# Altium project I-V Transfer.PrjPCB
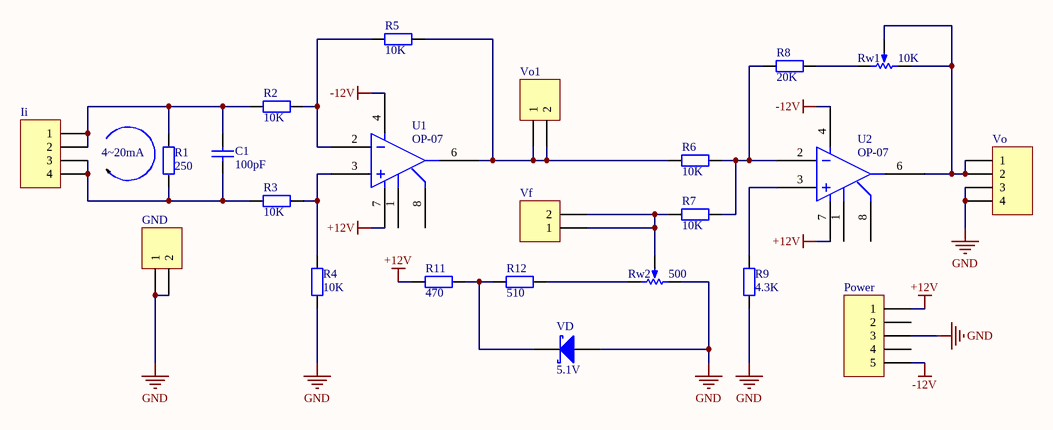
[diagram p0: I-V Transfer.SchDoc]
1 sheet, 23 parts. Net scope: global (net labels, ports and power ports of the same name join across sheets).
Board file: I-V Transfer.PcbDoc

## Sheet I-V Transfer.SchDoc
size A4

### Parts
C1  value 100pF  [RAD0.2]  (hidden comment: Cap)
GND  Header 2  [SIP-2]  (value not drawn)
Ii  Header 4  [SIP-4]  (value not drawn)
Power  Header 5  [POWER PLUG5]  (value not drawn)
R1  value 250  [AXIAL-0.4]  (hidden comment: Res2)
R2  value 10K  [AXIAL-0.4]  (hidden comment: Res2)
R3  value 10K  [AXIAL-0.4]  (hidden comment: Res2)
R4  value 10K  [AXIAL-0.4]  (hidden comment: Res2)
R5  value 10K  [AXIAL-0.4]  (hidden comment: Res2)
R6  value 10K  [AXIAL-0.4]  (hidden comment: Res2)
R7  value 10K  [AXIAL-0.4]  (hidden comment: Res2)
R8  value 20K  [AXIAL-0.4]  (hidden comment: Res2)
R9  value 4.3K  [AXIAL-0.4]  (hidden comment: Res2)
R11  value 470  [AXIAL-0.4]  (hidden comment: Res2)
R12  value 510  [AXIAL-0.4]  (hidden comment: Res2)
Rw1  value 10K  [VR5]  (hidden comment: RPot)
Rw2  value 500  [VR5]  (hidden comment: RPot)
U1  OP-07  [DIP-8]
U2  OP-07  [DIP-8]
VD  5.1V  [DIODE0.4]
Vf  Header 2  [SIP-2]  (value not drawn)
Vo  Header 4  [SIP-4]  (value not drawn)
Vo1  Header 2  [SIP-2]  (value not drawn)

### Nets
+12V: Power.1 R11.1 U1.7 U2.7
-12V: Power.5 U1.4 U2.4
GND: GND.1 GND.2 Power.3 R4.1 R9.1 Rw2.1(TOP) VD.1(A) Vo.3 Vo.4
NetC1_1: C1.1 Ii.3 Ii.4 R1.1 R3.1
NetC1_2: C1.2 Ii.1 Ii.2 R1.2 R2.1
NetR2_2: R2.2 R5.1 U1.2
NetR3_2: R3.2 R4.2 U1.3
NetR5_2: R5.2 R6.1 U1.6 Vo1.1 Vo1.2
NetR6_2: R6.2 R7.2 R8.1 U2.2
NetR7_1: R7.1 Rw2.2(TAP) Vf.1 Vf.2
NetR8_2: R8.2 Rw1.3(BOT)
NetR9_2: R9.2 U2.3
NetR11_2: R11.2 R12.1 VD.2(K)
NetR12_2: R12.2 Rw2.3(BOT)
NetRw1_1: Rw1.1(TOP) Rw1.2(TAP) U2.6 Vo.1 Vo.2

Not connected (* = marked no-connect by the designer): Power 2 4; U1 1 8; U2 1 8

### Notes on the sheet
- 4|0mA

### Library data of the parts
C1 = Cap: Capacitor
GND Vf Vo1 = Header 2: Header, 2-Pin
Ii Vo = Header 4: Header, 4-Pin
Power = Header 5: Header, 5-Pin
R1-R9 R11 R12 = Res2: Resistor
Rw1 Rw2 = RPot: Potentiometer; Sim Note: Enter the Resistance value and the set point into parameter fields.; Set Position: 0.5
VD = Diode 11DQ03: Schottky Rectifier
